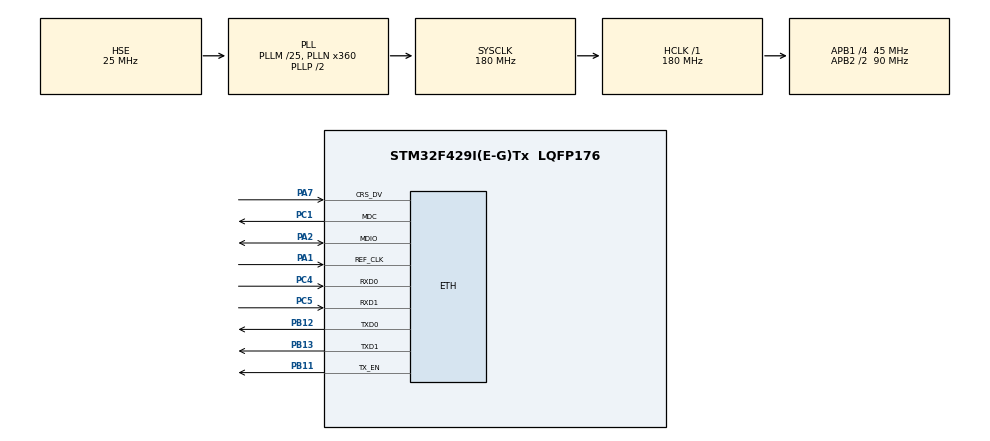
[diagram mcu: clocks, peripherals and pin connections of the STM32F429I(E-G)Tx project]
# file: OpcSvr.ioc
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ETH.MACAddr=66\:80\:E1\:11\:22\:33
ETH.MediaInterface=ETH_MEDIA_INTERFACE_RMII
FREERTOS.Tasks01=defaultTask,0,128,StartDefaultTask,Default,NULL
LWIP.GATEWAY_ADDRESS=192.168.030.001
LWIP.IP_ADDRESS=192.168.030.010
LWIP.LWIP_DHCP=0
LWIP.LWIP_DNS=1
LWIP.LWIP_NETIF_HOSTNAME=1
LWIP.NETMASK_ADDRESS=255.255.255.000
LWIP.Version=v2.0.3_Cube
Mcu.Family=STM32F4
Mcu.Name=STM32F429I(E-G)Tx
Mcu.Package=LQFP176
NVIC.ETH_IRQn=true\:5\:0\:false\:false\:true\:true\:false\:true
NVIC.PriorityGroup=NVIC_PRIORITYGROUP_4
PA1.Mode=RMII
PA1.Signal=ETH_REF_CLK
PA13.Mode=Serial_Wire
PA13.Signal=SYS_JTMS-SWDIO
PA14.Mode=Serial_Wire
PA14.Signal=SYS_JTCK-SWCLK
PA2.Mode=RMII
PA2.Signal=ETH_MDIO
PA7.Mode=RMII
PA7.Signal=ETH_CRS_DV
PB11.Mode=RMII
PB11.Signal=ETH_TX_EN
PB12.Mode=RMII
PB12.Signal=ETH_TXD0
PB13.Mode=RMII
PB13.Signal=ETH_TXD1
PC1.Mode=RMII
PC1.Signal=ETH_MDC
PC14/OSC32_IN.Mode=LSE-External-Oscillator
PC14/OSC32_IN.Signal=RCC_OSC32_IN
PC15/OSC32_OUT.Mode=LSE-External-Oscillator
PC15/OSC32_OUT.Signal=RCC_OSC32_OUT
PC4.Mode=RMII
PC4.Signal=ETH_RXD0
PC5.Mode=RMII
PC5.Signal=ETH_RXD1
PH0/OSC_IN.Mode=HSE-External-Oscillator
PH0/OSC_IN.Signal=RCC_OSC_IN
PH1/OSC_OUT.Mode=HSE-External-Oscillator
PH1/OSC_OUT.Signal=RCC_OSC_OUT
ProjectManager.HeapSize=0x200
ProjectManager.StackSize=0x400
ProjectManager.TargetToolchain=SW4STM32
RCC.48MHZClocksFreq_Value=90000000
RCC.AHBFreq_Value=180000000
RCC.APB1CLKDivider=RCC_HCLK_DIV4
RCC.APB1Freq_Value=45000000
RCC.APB1TimFreq_Value=90000000
RCC.APB2CLKDivider=RCC_HCLK_DIV2
RCC.APB2Freq_Value=90000000
RCC.APB2TimFreq_Value=180000000
RCC.CortexFreq_Value=180000000
RCC.HCLKFreq_Value=180000000
RCC.HSE_VALUE=25000000
RCC.HSI_VALUE=16000000
RCC.PLLM=25
RCC.PLLN=360
RCC.PLLSourceVirtual=RCC_PLLSOURCE_HSE
RCC.SYSCLKFreq_VALUE=180000000
RCC.SYSCLKSource=RCC_SYSCLKSOURCE_PLLCLK
RCC.VCOOutputFreq_Value=360000000
VP_FREERTOS_VS_CMSIS_V1.Mode=CMSIS_V1
VP_LWIP_VS_Enabled.Mode=Enabled
board=custom

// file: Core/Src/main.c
/* USER CODE BEGIN Header */
/**
 ******************************************************************************
 * @file           : main.c
 * @brief          : Main program body
 ******************************************************************************
 * @attention
 *
 * <h2><center>&copy; Copyright (c) 2019 STMicroelectronics.
 * All rights reserved.</center></h2>
 *
 * This software component is licensed by ST under Ultimate Liberty license
 * SLA0044, the "License"; You may not use this file except in compliance with
 * the License. You may obtain a copy of the License at:
 *                             www.st.com/SLA0044
 *
 ******************************************************************************
 */
/* USER CODE END Header */

#include "main.h"
#include "cmsis_os.h"
#include "lwip.h"
#include "open62541.h"

osThreadId defaultTaskHandle;

void SystemClock_Config(void);
static void MX_GPIO_Init(void);
void StartDefaultTask(void const * argument);

static void
beforeReadTime(UA_Server *server,
               const UA_NodeId *sessionId, void *sessionContext,
               const UA_NodeId *nodeid, void *nodeContext,
               const UA_NumericRange *range, const UA_DataValue *data) {
	  UA_LOG_INFO(UA_Log_Stdout, UA_LOGCATEGORY_USERLAND,
	                "The variable was updated");
}

static void
afterWriteTime(UA_Server *server,
               const UA_NodeId *sessionId, void *sessionContext,
               const UA_NodeId *nodeId, void *nodeContext,
               const UA_NumericRange *range, const UA_DataValue *data) {
    UA_LOG_INFO(UA_Log_Stdout, UA_LOGCATEGORY_USERLAND,
                "The variable was updated");

    if((*((UA_UInt32 *)data->value.data))==2){
    	HAL_GPIO_WritePin(GPIOH, GPIO_PIN_10|GPIO_PIN_11|GPIO_PIN_12, GPIO_PIN_SET);
    	HAL_GPIO_WritePin(GPIOH, GPIO_PIN_10, GPIO_PIN_RESET);
    }  else  if((*((UA_UInt32 *)data->value.data))==3){
    	HAL_GPIO_WritePin(GPIOH, GPIO_PIN_10|GPIO_PIN_11|GPIO_PIN_12, GPIO_PIN_SET);
    	HAL_GPIO_WritePin(GPIOH, GPIO_PIN_11, GPIO_PIN_RESET);
    } else  if((*((UA_UInt32 *)data->value.data))==4){
    	HAL_GPIO_WritePin(GPIOH, GPIO_PIN_10|GPIO_PIN_11|GPIO_PIN_12, GPIO_PIN_SET);
    	HAL_GPIO_WritePin(GPIOH, GPIO_PIN_12, GPIO_PIN_RESET);
    } else  if((*((UA_UInt32 *)data->value.data))==5){
    	HAL_GPIO_WritePin(GPIOH, GPIO_PIN_10|GPIO_PIN_11|GPIO_PIN_12, GPIO_PIN_SET);
    	HAL_GPIO_WritePin(GPIOH, GPIO_PIN_10|GPIO_PIN_11, GPIO_PIN_RESET);
    } else  if((*((UA_UInt32 *)data->value.data))==6){
    	HAL_GPIO_WritePin(GPIOH, GPIO_PIN_10|GPIO_PIN_11|GPIO_PIN_12, GPIO_PIN_SET);
    	HAL_GPIO_WritePin(GPIOH, GPIO_PIN_11|GPIO_PIN_12, GPIO_PIN_RESET);
    }else  if((*((UA_UInt32 *)data->value.data))==7){
    	HAL_GPIO_WritePin(GPIOH, GPIO_PIN_10|GPIO_PIN_11|GPIO_PIN_12, GPIO_PIN_SET);
    	HAL_GPIO_WritePin(GPIOH, GPIO_PIN_10|GPIO_PIN_12, GPIO_PIN_RESET);
    }else  if((*((UA_UInt32 *)data->value.data))==8){
    	HAL_GPIO_WritePin(GPIOH, GPIO_PIN_10|GPIO_PIN_11|GPIO_PIN_12, GPIO_PIN_SET);

    }else{
    	HAL_GPIO_WritePin(GPIOH, GPIO_PIN_10|GPIO_PIN_11|GPIO_PIN_12, GPIO_PIN_SET);
    	HAL_GPIO_WritePin(GPIOH, GPIO_PIN_10|GPIO_PIN_11|GPIO_PIN_12, GPIO_PIN_RESET);
    }

}

int i=0;
static void testCallback(UA_Server *server, void *data) {
	//UA_LOG_INFO(UA_Log_Stdout, UA_LOGCATEGORY_USERLAND, "testcallback");
	if(data!=NULL) {
		i=i+1;
	}
}
/* USER CODE BEGIN PFP */

void vApplicationMallocFailedHook() {
	for (;;) {
		vTaskDelay(pdMS_TO_TICKS(1000));
	}
}

void vApplicationStackOverflowHook(TaskHandle_t xTask, char *pcTaskName) {
	for (;;) {
		vTaskDelay(pdMS_TO_TICKS(1000));
	}
}

/* USER CODE END PFP */

int main(void) {

	/* MCU Configuration--------------------------------------------------------*/

	/* Reset of all peripherals, Initializes the Flash interface and the Systick. */
	HAL_Init();

	/* Configure the system clock */
	SystemClock_Config();

	/* Initialize all configured peripherals */
	MX_GPIO_Init();

	/* Create the thread(s) */
	/* definition and creation of defaultTask */
	osThreadDef(defaultTask, StartDefaultTask, osPriorityNormal, 0, 1024*12);
	defaultTaskHandle = osThreadCreate(osThread(defaultTask), NULL);

	/* Start scheduler */

	osKernelStart();

	/* We should never get here as control is now taken by the scheduler */

	/* Infinite loop */
	while (1) {

	}
}

void SystemClock_Config(void) {
	RCC_OscInitTypeDef RCC_OscInitStruct = { 0 };
	RCC_ClkInitTypeDef RCC_ClkInitStruct = { 0 };

	/** Configure the main internal regulator output voltage
	 */
	__HAL_RCC_PWR_CLK_ENABLE()
	;
	__HAL_PWR_VOLTAGESCALING_CONFIG(PWR_REGULATOR_VOLTAGE_SCALE1);
	/** Initializes the CPU, AHB and APB busses clocks
	 */
	RCC_OscInitStruct.OscillatorType = RCC_OSCILLATORTYPE_HSE;
	RCC_OscInitStruct.HSEState = RCC_HSE_ON;
	RCC_OscInitStruct.PLL.PLLState = RCC_PLL_ON;
	RCC_OscInitStruct.PLL.PLLSource = RCC_PLLSOURCE_HSE;
	RCC_OscInitStruct.PLL.PLLM = 25;
	RCC_OscInitStruct.PLL.PLLN = 360;
	RCC_OscInitStruct.PLL.PLLP = RCC_PLLP_DIV2;
	RCC_OscInitStruct.PLL.PLLQ = 4;
	if (HAL_RCC_OscConfig(&RCC_OscInitStruct) != HAL_OK) {
		Error_Handler();
	}
	/** Activate the Over-Drive mode
	 */
	if (HAL_PWREx_EnableOverDrive() != HAL_OK) {
		Error_Handler();
	}
	/** Initializes the CPU, AHB and APB busses clocks
	 */
	RCC_ClkInitStruct.ClockType = RCC_CLOCKTYPE_HCLK | RCC_CLOCKTYPE_SYSCLK
			| RCC_CLOCKTYPE_PCLK1 | RCC_CLOCKTYPE_PCLK2;
	RCC_ClkInitStruct.SYSCLKSource = RCC_SYSCLKSOURCE_PLLCLK;
	RCC_ClkInitStruct.AHBCLKDivider = RCC_SYSCLK_DIV1;
	RCC_ClkInitStruct.APB1CLKDivider = RCC_HCLK_DIV4;
	RCC_ClkInitStruct.APB2CLKDivider = RCC_HCLK_DIV2;

	if (HAL_RCC_ClockConfig(&RCC_ClkInitStruct, FLASH_LATENCY_5) != HAL_OK) {
		Error_Handler();
	}
}

static void MX_GPIO_Init(void) {
	 GPIO_InitTypeDef GPIO_InitStruct = {0};

	/* GPIO Ports Clock Enable */
	__HAL_RCC_GPIOC_CLK_ENABLE()
	;
	__HAL_RCC_GPIOH_CLK_ENABLE()
	;
	__HAL_RCC_GPIOA_CLK_ENABLE()
	;
	__HAL_RCC_GPIOB_CLK_ENABLE()
	;

	 HAL_GPIO_WritePin(GPIOH, GPIO_PIN_10|GPIO_PIN_11|GPIO_PIN_12, GPIO_PIN_RESET);

	 /*Configure GPIO pins : PE3 PE4 */
	  GPIO_InitStruct.Pin = GPIO_PIN_10|GPIO_PIN_11|GPIO_PIN_12;
	  GPIO_InitStruct.Mode = GPIO_MODE_OUTPUT_PP;
	  GPIO_InitStruct.Pull = GPIO_NOPULL;
	  GPIO_InitStruct.Speed = GPIO_SPEED_FREQ_LOW;
	  HAL_GPIO_Init(GPIOH, &GPIO_InitStruct);

}

/* USER CODE BEGIN 4 */
UA_Boolean running = true;
/* USER CODE END 4 */

void StartDefaultTask(void const * argument) {
	/* init code for LWIP */
	MX_LWIP_Init();

	UA_Server *server = UA_Server_new();
	UA_ServerConfig *config=UA_Server_getConfig(server);

	UA_ServerConfig_setMinimalCustomBuffer(config,
	                                       4840,
	                                       NULL,
	                                       1024*2,
										   1024*2);

	UA_ServerConfig_setDefault(config);
    UA_VariableAttributes attr = UA_VariableAttributes_default;
    UA_Int32 myInteger = 1;
    UA_Variant_setScalar(&attr.value, &myInteger, &UA_TYPES[UA_TYPES_INT32]);
    attr.description = UA_LOCALIZEDTEXT("en-US","LightMagic");
    attr.displayName = UA_LOCALIZEDTEXT("en-US","LightMagic");
    attr.dataType = UA_TYPES[UA_TYPES_INT32].typeId;

    attr.accessLevel = UA_ACCESSLEVELMASK_READ | UA_ACCESSLEVELMASK_WRITE;

    /* Add the variable node to the information model */
    UA_NodeId myIntegerNodeId = UA_NODEID_STRING(1, "LightMagic");
    UA_QualifiedName myIntegerName = UA_QUALIFIEDNAME(1, "LightMagic");
    UA_NodeId parentNodeId = UA_NODEID_NUMERIC(0, UA_NS0ID_OBJECTSFOLDER);
    UA_NodeId parentReferenceNodeId = UA_NODEID_NUMERIC(0, UA_NS0ID_ORGANIZES);
    UA_Server_addVariableNode(server, myIntegerNodeId, parentNodeId,
                              parentReferenceNodeId, myIntegerName,
                              UA_NODEID_NUMERIC(0, UA_NS0ID_BASEDATAVARIABLETYPE), attr, NULL, NULL);

    UA_Server_addRepeatedCallback(server, testCallback, NULL, 2000, NULL); /* call every 2 sec */

    //UA_NodeId currentNodeId = UA_NODEID_STRING(1, "current-time");
	UA_ValueCallback callback;
	callback.onRead = beforeReadTime;
	callback.onWrite = afterWriteTime;
	UA_Server_setVariableNode_valueCallback(server, myIntegerNodeId, callback);

	UA_StatusCode retval = UA_Server_run(server, &running);

	UA_Server_delete(server);
}

void Error_Handler(void) {
}

/************************ (C) COPYRIGHT STMicroelectronics *****END OF FILE****/
